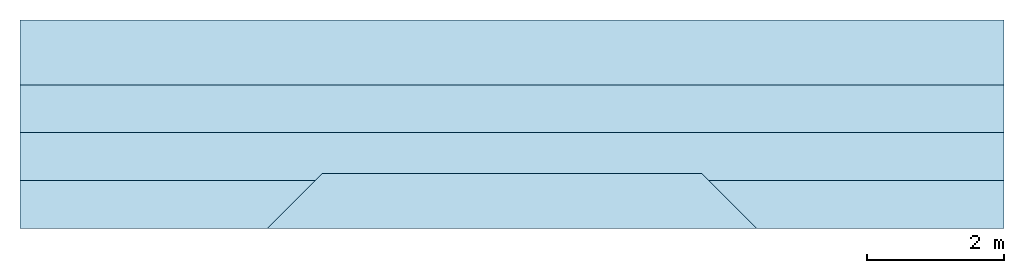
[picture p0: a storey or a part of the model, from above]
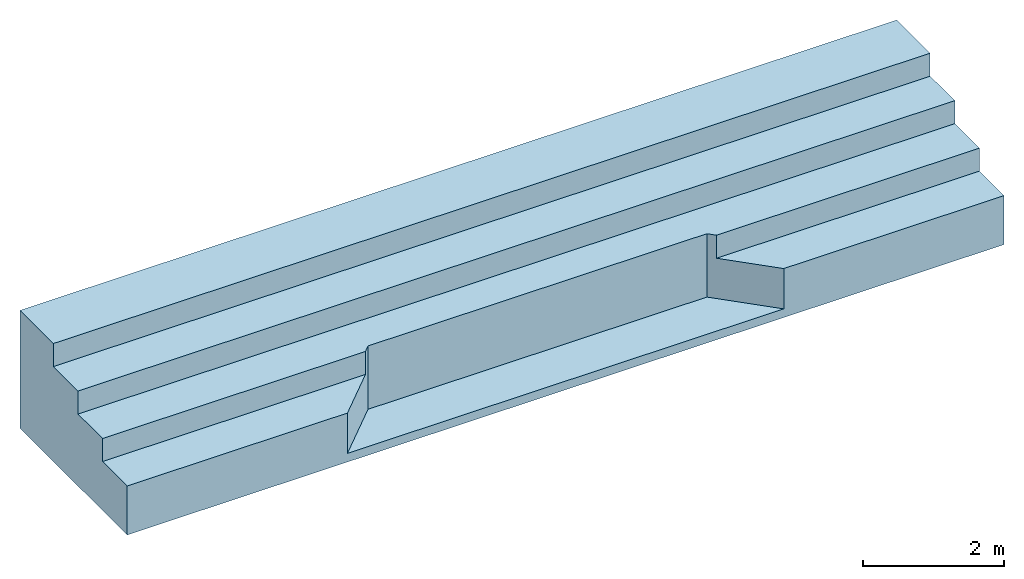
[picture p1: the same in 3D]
Properties of the parts of a building model (IFC4)

# File
Description: ViewDefinition [ReferenceView_V1.2], RevitIdentifiers [ContentGUID: 659c343b-a0ff-48e8-a1a8-6473eb1fbd3c, VersionGUID: c3321544-eab9-466d-ad36-07a7d4ca91c6, NumberOfSaves: 43], CoordinateReference [CoordinateBase: Coordenadas compartilhadas], ExchangeRequirement [Structural]
File name: PADRAO-GIN-CON-ARRIMO ARQ.ifc
Time: 2025-06-02T14:21:33-03:00
Written by: ODA SDAI 24.12
Made in: Autodesk Revit 25.4.0.32 (PTB) - IFC 25.4.0.32

# IfcProject, ------
LongName: CONTENÇÃO DE ARQUIBANCADA - GINÁSIO PADRÃO; Phase: EXECUTIVO

# IfcSite, Default
RefLatitude: -15, -52, 0, -120620; RefLongitude: -47, -55, 0, -114440; RefElevation: 0 cm
Pset_SiteCommon - Reference: Informações do projeto

# IfcBuilding, CONTENÇÃO DE ARQUIBANCADA - GINÁSIO PADRÃO
LongName: CONTENÇÃO DE ARQUIBANCADA - GINÁSIO PADRÃO
Pset_BuildingCommon - Reference: Informações do projeto; NumberOfStoreys: 3
Pset_BuildingElementProxyCommon - Reference: Informações do projeto; IsExternal: no
Pset_BuildingStoreyCommon - Reference: Informações do projeto; sets with these values: 2

# IfcBuildingStorey: Nível:Cabeça de 8 mm (3)
In: CONTENÇÃO DE ARQUIBANCADA - GINÁSIO PADRÃO
Pset_BuildingStoreyCommon - Reference: Cabeça de 8 mm
Name | LongName | Elevation (cm)
Nível 3 | Nível 3 | -100
Nível 1 | Nível 1 | 0
Nível 2 | Nível 2 | 300

# IfcBeam: Concreto-Viga Retangular1:30x30 (3)
In: Nível 1
Type - PredefinedType: BEAM; Material: Concreto C-30
Type - Pset_BeamCommon - LoadBearing: yes
Pset_BeamCommon - IsExternal: no; Slope: 0 deg; Reference: 30x30; Roll: 0 deg
Pset_EnvironmentalImpactIndicators - Reference: 30x30; sets with these values: 2
Name (Concreto-Viga Retangular1:30x30:...) | Span (cm) | CrossSectionArea (m2) | NetSurfaceArea (m2) | NetVolume (m3)
558076 | 552.241 | 3.5752 | 7.15039 | 0.463192
558094 | 105.208 | 0.584687 | 1.16937 | 0.0685367
558128 | 105.161 | 0.58443 | 1.16886 | 0.0685003

# IfcBuildingElementProxy: Bloco de Concreto - Canaleta Inteira:Família 20 x 40 - Classe A (23)
In: Nível 1
Type - Material: Concreto, aerado
Type - Pset_ManufacturerTypeInformation - Manufacturer: http://www.blocobrasil.com.br/site/fabricantes-de-blocos-e-pisos-intertravados/
Pset_BuildingElementProxyCommon - IsExternal: no; Reference: Família 20 x 40 - Classe A
Pset_EnvironmentalImpactIndicators - Reference: Família 20 x 40 - Classe A
Qto_BuildingElementProxyQuantities - NetSurfaceArea: 0.541113 m2; NetVolume: 0.00634527 m3
Name (Bloco de Concreto - Canaleta Inteira:Família 20 x 40 - Classe A:...)
567616
568056
568057
568058
568059
568088
568089
568090
568111
568112
568113
568114
568126
568127
568128
568146
568147
568148
568149
568161
568162
568163
568207

# IfcBuildingElementProxy: Bloco de Concreto - Inteiro:Família 20 x 40 - Classe A (52)
In: Nível 1
Type - Material: Concreto, aerado
Type - Pset_ManufacturerTypeInformation - Manufacturer: http://www.blocobrasil.com.br/site/fabricantes-de-blocos-e-pisos-intertravados/
Pset_BuildingElementProxyCommon - IsExternal: no; Reference: Família 20 x 40 - Classe A
Pset_EnvironmentalImpactIndicators - Reference: Família 20 x 40 - Classe A
Qto_BuildingElementProxyQuantities - NetSurfaceArea: 0.493124 m2; NetVolume: 0.0067089 m3
Name (Bloco de Concreto - Inteiro:Família 20 x 40 - Classe A:...)
565329
565978
566817
566818
566819
566820
566831
566832
566833
566834
566852
566853
566854
566855
566892
567367
567599
567600
567754
567755
567756
568062
568063
568064
568082
568083
568084
568085
568108
568109
568110
568117
568118
568119
568120
568121
568122
568123
568143
568144
568145
568152
568153
568154
568155
568156
568157
568158
568199
568202
568203
568204

# IfcBuildingElementProxy: Bloco de Concreto - Meia Canaleta:Família 20 x 40 - Classe A (10)
In: Nível 1
Type - Material: Concreto, aerado
Type - Pset_ManufacturerTypeInformation - Manufacturer: http://www.blocobrasil.com.br/site/fabricantes-de-blocos-e-pisos-intertravados/
Pset_BuildingElementProxyCommon - IsExternal: no; Reference: Família 20 x 40 - Classe A
Pset_EnvironmentalImpactIndicators - Reference: Família 20 x 40 - Classe A
Qto_BuildingElementProxyQuantities - NetSurfaceArea: 0.23009 m2; NetVolume: 0.00290116 m3
Name (Bloco de Concreto - Meia Canaleta:Família 20 x 40 - Classe A:...)
567614
567615
568086
568087
568124
568125
568159
568160
568205
568206

# IfcBuildingElementProxy: Bloco de Concreto - Meio:Família 20 x 40 - Classe A (16)
In: Nível 1
Type - Material: Concreto, aerado
Type - Pset_ManufacturerTypeInformation - Manufacturer: http://www.blocobrasil.com.br/site/fabricantes-de-blocos-e-pisos-intertravados/
Pset_BuildingElementProxyCommon - IsExternal: no; Reference: Família 20 x 40 - Classe A
Pset_EnvironmentalImpactIndicators - Reference: Família 20 x 40 - Classe A
Qto_BuildingElementProxyQuantities - NetSurfaceArea: 0.276622 m2; NetVolume: 0.0035929 m3
Name (Bloco de Concreto - Meio:Família 20 x 40 - Classe A:...)
567094
567338
567658
567717
568060
568061
568106
568107
568115
568116
568141
568142
568150
568151
568200
568201

# IfcBuildingElementProxy: Modelos genéricos 1:Modelos genéricos 1, Modelos genéricos 1:Modelos genéricos 1:567017
In: Nível 1
Type - Material: <Unnamed>
Pset_BuildingElementProxyCommon - IsExternal: no; Reference: Modelos genéricos 1
Pset_EnvironmentalImpactIndicators - Reference: Modelos genéricos 1
Qto_BuildingElementProxyQuantities - NetSurfaceArea: 30.9839 m2; NetVolume: 7.27395 m3

# IfcColumn: M_Concreto-Retangular-Coluna1:20x30 (6)
In: Nível 1
Type - PredefinedType: COLUMN; Material: Concreto C-30
Type - Pset_ColumnCommon - LoadBearing: yes
Qto_ColumnBaseQuantities - CrossSectionArea: 0.06 m2
Pset_ColumnCommon - Reference: 20x30; IsExternal: no
Pset_EnvironmentalImpactIndicators - Reference: 20x30; sets with these values: 2
Name (M_Concreto-Retangular-Coluna1:20x30:...) | Length (cm) | OuterSurfaceArea (m2) | GrossVolume (m3) = NetVolume (m3)
555757 | 150 | 1.5 | 0.09
555761 | 110 | 1.1 | 0.066
555764 | 150 | 1.5 | 0.09 | Pset_ColumnCommon - Slope: 0 deg
555767 | 110 | 1.1 | 0.066 | Pset_ColumnCommon - Slope: 0 deg
565785 | 150 | 1.5 | 0.09
565798 | 150 | 1.5 | 0.09 | Pset_ColumnCommon - Slope: 0 deg

# IfcReinforcingBar: Barra do vergalhão:10 CA-50 (39)
In: Nível 3
Pset_EnvironmentalImpactIndicators - Reference: 10 CA-50; sets with these values: 2
Name (Barra do vergalhão:10 CA-50 :...)
 Forma 01:632751
 Forma 01:633253
 Forma 01:633268
 Forma 01:648456
 Forma 01:649545
 Forma 01:649674
 Forma 01:649675
 Forma 01:649677
 Forma 01:649678
 Forma 01:649680
 Forma 01:649681
 Forma 01:649683
 Forma 01:649684
 Forma 01:649686
 Forma 01:649687
 Forma 19:650507
 Forma 19:650796
 Forma 19:650819
 Forma 19:650820
 Forma 19:650881
 Forma 19:650882
 Forma 19:650883
 Forma 19:650884
 Forma 19:650886
 Forma 19:650887
 Forma 19:650888
 Forma 19:650889
 Forma 19:650891
 Forma 19:650892
 Forma 19:650893
 Forma 19:650894
 Forma 19:650896
 Forma 19:650897
 Forma 19:650898
 Forma 19:650899
 Forma 19:650901
 Forma 19:650902
 Forma 19:650903
 Forma 19:650904

# IfcReinforcingBar: Barra do vergalhão:12.5 CA-50 (34)
Pset_EnvironmentalImpactIndicators - Reference: 12.5 CA-50; sets with these values: 2
Name (Barra do vergalhão:12.5 CA-50 :...) | In
 Forma 01:635254 | Nível 1
 Forma 01:635535 | Nível 1
 Forma 01:635637 | Nível 1
 Forma 01:635638 | Nível 1
 Forma 01:637350 | Nível 1
 Forma 01:637784 | Nível 1
 Forma 01:638170 | Nível 1
 Forma 01:638171 | Nível 1
 Forma 01:640205 | Nível 3
 Forma 01:640286 | Nível 3
 Forma 01:640631 | Nível 3
 Forma 01:640632 | Nível 3
 Forma 01:640635 | Nível 3
 Forma 01:640636 | Nível 3
 Forma 01:640640 | Nível 3
 Forma 01:640641 | Nível 3
 Forma 01:640701 | Nível 3
 Forma 01:640702 | Nível 3
 Forma 01:640706 | Nível 3
 Forma 01:640707 | Nível 3
 Forma 01:641535 | Nível 1
 Forma 01:641536 | Nível 1
 Forma 01:641537 | Nível 1
 Forma 01:641538 | Nível 1
 Forma 01:641551 | Nível 1
 Forma 01:641552 | Nível 1
 Forma 01:641553 | Nível 1
 Forma 01:641554 | Nível 1
 Forma 16:656190 | Nível 3
 Forma 16:657339 | Nível 3
 Forma 16:658206 | Nível 3
 Forma 16:658253 | Nível 3
 Forma 16:660648 | Nível 3
 Forma 16:660649 | Nível 3

# IfcReinforcingBar: Barra do vergalhão:6.3 CA-50 (17)
In: Nível 3
Pset_EnvironmentalImpactIndicators - Reference: 6.3 CA-50; sets with these values: 2
Name (Barra do vergalhão:6.3 CA-50 :...)
 Forma 22:639805
 Forma 22:640630
 Forma 22:640634
 Forma 22:640639
 Forma 22:640700
 Forma 22:640705
 Forma 33:644297
 Forma 33:648401
 Forma 33:648409
 Forma 33:648417
 Forma 33:649805
 Forma 33:649867
 Forma 22:655642
 Forma 22:655746
 Forma 22:655757
 Forma 22:657933
 Forma 22:659656

# IfcSlab: Estaca de concreto:EST30-3m (6)
In: Nível 1
Type - PredefinedType: BASESLAB; Material: Concreto C-25
Classification: 540 (Uniformat)
Pset_EnvironmentalImpactIndicators - Reference: EST30-3m; sets with these values: 2
Pset_SlabCommon - IsExternal: no; Reference: EST30-3m
Qto_SlabBaseQuantities - Depth: 300 cm; Perimeter: 94.2478 cm; GrossArea: 0.0706764 m2; NetArea: 0.0706764 m2; GrossVolume: 0.212029 m3; NetVolume: 0.212047 m3
Name (Estaca de concreto:EST30-3m:...) | PitchAngle (deg)
559735 | 0
559918
560231 | 0
560358 | 0
628680 | 0
628696 | 0

# IfcSlab: Piso:Genérico 250 mm, Piso:Genérico 250 mm:556561
In: Nível 1
Type - PredefinedType: FLOOR; Material: Material pré-definido de piso
Pset_EnvironmentalImpactIndicators - Reference: Genérico 250 mm; sets with these values: 2
Pset_SlabCommon - IsExternal: no; LoadBearing: yes; PitchAngle: 0 deg; Reference: Genérico 250 mm
Qto_SlabBaseQuantities - Depth: 25 cm; Perimeter: 3258.01 cm; GrossArea: 27.3085 m2; NetArea: 27.3085 m2; GrossVolume: 6.82711 m3; NetVolume: 6.82711 m3

# IfcSlab: Piso:piso 15, Piso:piso 15:556478
In: Nível 1
Type - PredefinedType: FLOOR; Material: Concreto, Moldado in loco, cinza
Type - Pset_SlabCommon - ThermalTransmittance: 6.97333 kg/K/s3
Pset_EnvironmentalImpactIndicators - Reference: piso 15; sets with these values: 2
Pset_SlabCommon - IsExternal: no; LoadBearing: yes; Reference: piso 15; PitchAngle: 0 deg
Qto_SlabBaseQuantities - Depth: 15 cm; Perimeter: 3258.01 cm; GrossArea: 27.3085 m2; NetArea: 27.3085 m2; GrossVolume: 4.09627 m3; NetVolume: 4.09627 m3

# IfcSlab: Pisos 1:Pisos 1, Pisos 1:Pisos 1:568458
In: Nível 2
Type - PredefinedType: FLOOR; Material: Terra
Pset_EnvironmentalImpactIndicators - Reference: Pisos 1; sets with these values: 2
Pset_SlabCommon - IsExternal: no; Reference: Pisos 1
Qto_SlabBaseQuantities - GrossArea: 5.42084 m2; NetArea: 5.42084 m2; NetVolume: 62.0525 m3

# IfcStair: Escadas 1:Escadas 1, Escadas 1:Escadas 1:556475
In: Nível 1
Type - Pset_StairCommon - NumberOfRiser: 0; NumberOfTreads: 0; NosingLength: 0 cm
Type - Pset_StairFlightCommon - NosingLength: 0 cm; NumberOfRiser: 0; NumberOfTreads: 0
Material: <Unnamed>
Pset_EnvironmentalImpactIndicators - Reference: Escadas 1; sets with these values: 2
Pset_StairCommon - IsExternal: no; Reference: Escadas 1
